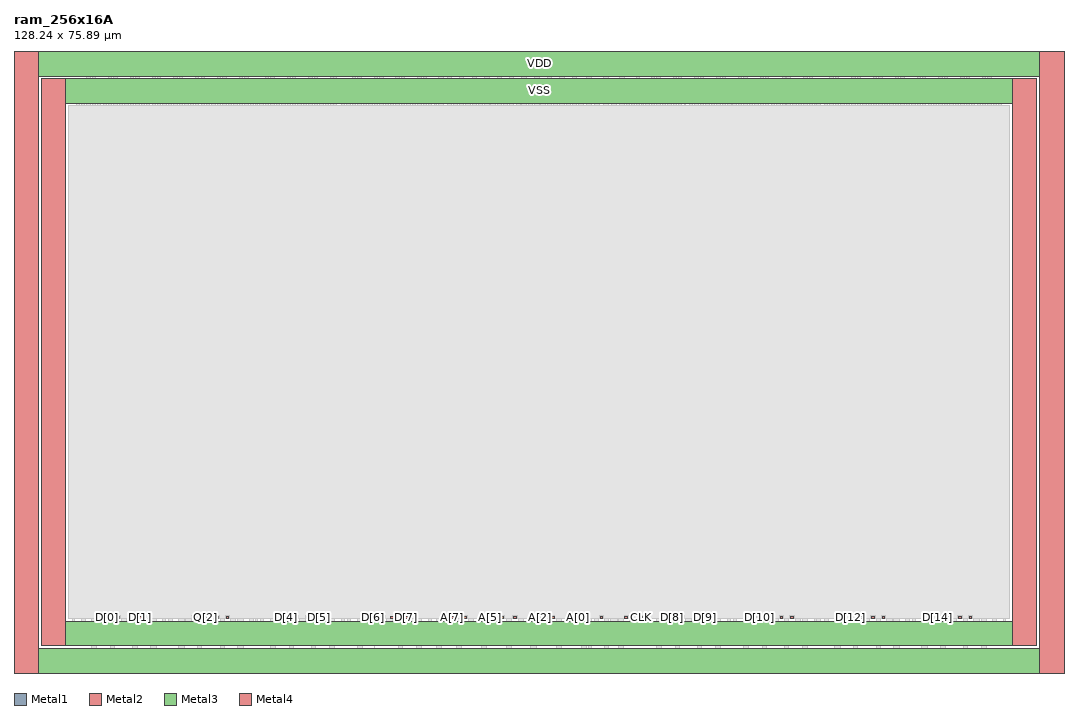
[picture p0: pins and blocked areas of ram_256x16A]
MACRO ram_256x16A
  CLASS RING ;
  FOREIGN ram_256x16A 0 0 ;
  ORIGIN 0 0 ;
  SIZE 128.24 BY 75.89 ;
  SYMMETRY X Y R90 ;
  PIN A[0]
    DIRECTION INPUT ;
    USE SIGNAL ;
    ANTENNAGATEAREA  0.039 ;
    PORT
      LAYER Metal1 ;
        RECT 68.69 6.6 69.02 6.93 ;
      LAYER Metal2 ;
        RECT 68.69 6.6 69.02 6.93 ;
      LAYER Metal3 ;
        RECT 68.69 6.6 69.02 6.93 ;
      LAYER Metal4 ;
        RECT 68.69 6.6 69.02 6.93 ;
      END
    END A[0]
  PIN A[1]
    DIRECTION INPUT ;
    USE SIGNAL ;
    ANTENNAGATEAREA  0.039 ;
    PORT
      LAYER Metal1 ;
        RECT 65.63 6.6 65.96 6.93 ;
      LAYER Metal2 ;
        RECT 65.63 6.6 65.96 6.93 ;
      LAYER Metal3 ;
        RECT 65.63 6.6 65.96 6.93 ;
      LAYER Metal4 ;
        RECT 65.63 6.6 65.96 6.93 ;
      END
    END A[1]
  PIN A[2]
    DIRECTION INPUT ;
    USE SIGNAL ;
    ANTENNAGATEAREA  0.039 ;
    PORT
      LAYER Metal1 ;
        RECT 64.08 6.6 64.41 6.93 ;
      LAYER Metal2 ;
        RECT 64.08 6.6 64.41 6.93 ;
      LAYER Metal3 ;
        RECT 64.08 6.6 64.41 6.93 ;
      LAYER Metal4 ;
        RECT 64.08 6.6 64.41 6.93 ;
      END
    END A[2]
  PIN A[3]
    ANTENNAGATEAREA  0.039 ;
    DIRECTION INPUT ;
    USE SIGNAL ;
    PORT
      LAYER Metal1 ;
        RECT 61.02 6.6 61.35 6.93 ;
      LAYER Metal2 ;
        RECT 61.02 6.6 61.35 6.93 ;
      LAYER Metal3 ;
        RECT 61.02 6.6 61.35 6.93 ;
      LAYER Metal4 ;
        RECT 61.02 6.6 61.35 6.93 ;
      END
    END A[3]
  PIN A[4]
    DIRECTION INPUT ;
    ANTENNAGATEAREA  0.039 ;
    USE SIGNAL ;
    PORT
      LAYER Metal1 ;
        RECT 59.51 6.6 59.84 6.93 ;
      LAYER Metal2 ;
        RECT 59.51 6.6 59.84 6.93 ;
      LAYER Metal3 ;
        RECT 59.51 6.6 59.84 6.93 ;
      LAYER Metal4 ;
        RECT 59.51 6.6 59.84 6.93 ;
      END
    END A[4]
  PIN A[5]
    ANTENNAGATEAREA  0.039 ;
    DIRECTION INPUT ;
    USE SIGNAL ;
    PORT
      LAYER Metal1 ;
        RECT 57.96 6.6 58.29 6.93 ;
      LAYER Metal2 ;
        RECT 57.96 6.6 58.29 6.93 ;
      LAYER Metal3 ;
        RECT 57.96 6.6 58.29 6.93 ;
      LAYER Metal4 ;
        RECT 57.96 6.6 58.29 6.93 ;
      END
    END A[5]
  PIN A[6]
    ANTENNAGATEAREA  0.039 ;
    DIRECTION INPUT ;
    USE SIGNAL ;
    PORT
      LAYER Metal1 ;
        RECT 54.9 6.6 55.23 6.93 ;
      LAYER Metal2 ;
        RECT 54.9 6.6 55.23 6.93 ;
      LAYER Metal3 ;
        RECT 54.9 6.6 55.23 6.93 ;
      LAYER Metal4 ;
        RECT 54.9 6.6 55.23 6.93 ;
      END
    END A[6]
  PIN A[7]
    ANTENNAGATEAREA  0.039 ;
    DIRECTION INPUT ;
    USE SIGNAL ;
    PORT
      LAYER Metal1 ;
        RECT 53.39 6.6 53.72 6.93 ;
      LAYER Metal2 ;
        RECT 53.39 6.6 53.72 6.93 ;
      LAYER Metal3 ;
        RECT 53.39 6.6 53.72 6.93 ;
      LAYER Metal4 ;
        RECT 53.39 6.6 53.72 6.93 ;
      END
    END A[7]
  PIN CEN
    ANTENNAGATEAREA  0.039 ;
    DIRECTION INPUT ;
    USE SIGNAL ;
    PORT
      LAYER Metal1 ;
        RECT 71.59 6.6 71.92 6.93 ;
      LAYER Metal2 ;
        RECT 71.59 6.6 71.92 6.93 ;
      LAYER Metal3 ;
        RECT 71.59 6.6 71.92 6.93 ;
      LAYER Metal4 ;
        RECT 71.59 6.6 71.92 6.93 ;
      END
    END CEN
  PIN CLK
    DIRECTION INPUT ;
    ANTENNAGATEAREA  0.039 ;
    USE CLOCK ;
    PORT
      LAYER Metal1 ;
        RECT 76.47 6.6 76.8 6.93 ;
      LAYER Metal2 ;
        RECT 76.47 6.6 76.8 6.93 ;
      LAYER Metal3 ;
        RECT 76.47 6.6 76.8 6.93 ;
      LAYER Metal4 ;
        RECT 76.47 6.6 76.8 6.93 ;
      END
    END CLK
  PIN D[0]
    ANTENNAGATEAREA  0.039 ;
    DIRECTION INPUT ;
    USE SIGNAL ;
    PORT
      LAYER Metal1 ;
        RECT 11.24 6.6 11.57 6.93 ;
      LAYER Metal2 ;
        RECT 11.24 6.6 11.57 6.93 ;
      LAYER Metal3 ;
        RECT 11.24 6.6 11.57 6.93 ;
      LAYER Metal4 ;
        RECT 11.24 6.6 11.57 6.93 ;
      END
    END D[0]
  PIN D[10]
    DIRECTION INPUT ;
    USE SIGNAL ;
    ANTENNAGATEAREA  0.039 ;
    PORT
      LAYER Metal1 ;
        RECT 90.84 6.6 91.17 6.93 ;
      LAYER Metal2 ;
        RECT 90.84 6.6 91.17 6.93 ;
      LAYER Metal3 ;
        RECT 90.84 6.6 91.17 6.93 ;
      LAYER Metal4 ;
        RECT 90.84 6.6 91.17 6.93 ;
      END
    END D[10]
  PIN D[11]
    DIRECTION INPUT ;
    USE SIGNAL ;
    ANTENNAGATEAREA  0.039 ;
    PORT
      LAYER Metal1 ;
        RECT 94.86 6.6 95.19 6.93 ;
      LAYER Metal2 ;
        RECT 94.86 6.6 95.19 6.93 ;
      LAYER Metal3 ;
        RECT 94.86 6.6 95.19 6.93 ;
      LAYER Metal4 ;
        RECT 94.86 6.6 95.19 6.93 ;
      END
    END D[11]
  PIN D[12]
    DIRECTION INPUT ;
    ANTENNAGATEAREA  0.039 ;
    USE SIGNAL ;
    PORT
      LAYER Metal1 ;
        RECT 102.01 6.6 102.34 6.93 ;
      LAYER Metal2 ;
        RECT 102.01 6.6 102.34 6.93 ;
      LAYER Metal3 ;
        RECT 102.01 6.6 102.34 6.93 ;
      LAYER Metal4 ;
        RECT 102.01 6.6 102.34 6.93 ;
      END
    END D[12]
  PIN D[13]
    DIRECTION INPUT ;
    USE SIGNAL ;
    ANTENNAGATEAREA  0.039 ;
    PORT
      LAYER Metal1 ;
        RECT 106.03 6.6 106.36 6.93 ;
      LAYER Metal2 ;
        RECT 106.03 6.6 106.36 6.93 ;
      LAYER Metal3 ;
        RECT 106.03 6.6 106.36 6.93 ;
      LAYER Metal4 ;
        RECT 106.03 6.6 106.36 6.93 ;
      END
    END D[13]
  PIN D[14]
    DIRECTION INPUT ;
    USE SIGNAL ;
    ANTENNAGATEAREA  0.039 ;
    PORT
      LAYER Metal1 ;
        RECT 112.65 6.6 112.98 6.93 ;
      LAYER Metal2 ;
        RECT 112.65 6.6 112.98 6.93 ;
      LAYER Metal3 ;
        RECT 112.65 6.6 112.98 6.93 ;
      LAYER Metal4 ;
        RECT 112.65 6.6 112.98 6.93 ;
      END
    END D[14]
  PIN D[15]
    ANTENNAGATEAREA  0.039 ;
    DIRECTION INPUT ;
    USE SIGNAL ;
    PORT
      LAYER Metal1 ;
        RECT 116.67 6.6 117.00 6.93 ;
      LAYER Metal2 ;
        RECT 116.67 6.6 117.00 6.93 ;
      LAYER Metal3 ;
        RECT 116.67 6.6 117.00 6.93 ;
      LAYER Metal4 ;
        RECT 116.67 6.6 117.00 6.93 ;
      END
    END D[15]
  PIN D[1]
    DIRECTION INPUT ;
    USE SIGNAL ;
    ANTENNAGATEAREA  0.039 ;
    PORT
      LAYER Metal1 ;
        RECT 15.26 6.6 15.59 6.93 ;
      LAYER Metal2 ;
        RECT 15.26 6.6 15.59 6.93 ;
      LAYER Metal3 ;
        RECT 15.26 6.6 15.59 6.93 ;
      LAYER Metal4 ;
        RECT 15.26 6.6 15.59 6.93 ;
      END
    END D[1]
  PIN D[2]
    DIRECTION INPUT ;
    USE SIGNAL ;
    ANTENNAGATEAREA  0.039 ;
    PORT
      LAYER Metal1 ;
        RECT 21.88 6.6 22.21 6.93 ;
      LAYER Metal2 ;
        RECT 21.88 6.6 22.21 6.93 ;
      LAYER Metal3 ;
        RECT 21.88 6.6 22.21 6.93 ;
      LAYER Metal4 ;
        RECT 21.88 6.6 22.21 6.93 ;
      END
    END D[2]
  PIN D[3]
    DIRECTION INPUT ;
    USE SIGNAL ;
    ANTENNAGATEAREA  0.039 ;
    PORT
      LAYER Metal1 ;
        RECT 25.9 6.6 26.23 6.93 ;
      LAYER Metal2 ;
        RECT 25.9 6.6 26.23 6.93 ;
      LAYER Metal3 ;
        RECT 25.9 6.6 26.23 6.93 ;
      LAYER Metal4 ;
        RECT 25.9 6.6 26.23 6.93 ;
      END
    END D[3]
  PIN D[4]
    DIRECTION INPUT ;
    USE SIGNAL ;
    ANTENNAGATEAREA  0.039 ;
    PORT
      LAYER Metal1 ;
        RECT 33.05 6.6 33.38 6.93 ;
      LAYER Metal2 ;
        RECT 33.05 6.6 33.38 6.93 ;
      LAYER Metal3 ;
        RECT 33.05 6.6 33.38 6.93 ;
      LAYER Metal4 ;
        RECT 33.05 6.6 33.38 6.93 ;
      END
    END D[4]
  PIN D[5]
    DIRECTION INPUT ;
    USE SIGNAL ;
    ANTENNAGATEAREA  0.039 ;
    PORT
      LAYER Metal1 ;
        RECT 37.07 6.6 37.4 6.93 ;
      LAYER Metal2 ;
        RECT 37.07 6.6 37.4 6.93 ;
      LAYER Metal3 ;
        RECT 37.07 6.6 37.4 6.93 ;
      LAYER Metal4 ;
        RECT 37.07 6.6 37.4 6.93 ;
      END
    END D[5]
  PIN D[6]
    DIRECTION INPUT ;
    USE SIGNAL ;
    ANTENNAGATEAREA  0.039 ;
    PORT
      LAYER Metal1 ;
        RECT 43.69 6.6 44.02 6.93 ;
      LAYER Metal2 ;
        RECT 43.69 6.6 44.02 6.93 ;
      LAYER Metal3 ;
        RECT 43.69 6.6 44.02 6.93 ;
      LAYER Metal4 ;
        RECT 43.69 6.6 44.02 6.93 ;
      END
    END D[6]
  PIN D[7]
    DIRECTION INPUT ;
    USE SIGNAL ;
    ANTENNAGATEAREA  0.039 ;
    PORT
      LAYER Metal1 ;
        RECT 47.71 6.6 48.04 6.93 ;
      LAYER Metal2 ;
        RECT 47.71 6.6 48.04 6.93 ;
      LAYER Metal3 ;
        RECT 47.71 6.6 48.04 6.93 ;
      LAYER Metal4 ;
        RECT 47.71 6.6 48.04 6.93 ;
      END
    END D[7]
  PIN D[8]
    DIRECTION INPUT ;
    USE SIGNAL ;
    ANTENNAGATEAREA  0.039 ;
    PORT
      LAYER Metal1 ;
        RECT 80.20 6.6 80.53 6.93 ;
      LAYER Metal2 ;
        RECT 80.20 6.6 80.53 6.93 ;
      LAYER Metal3 ;
        RECT 80.20 6.6 80.53 6.93 ;
      LAYER Metal4 ;
        RECT 80.20 6.6 80.53 6.93 ;
      END
    END D[8]
  PIN D[9]
    DIRECTION INPUT ;
    USE SIGNAL ;
    ANTENNAGATEAREA  0.039 ;
    PORT
      LAYER Metal1 ;
        RECT 84.22 6.6 84.55 6.93 ;
      LAYER Metal2 ;
        RECT 84.22 6.6 84.55 6.93 ;
      LAYER Metal3 ;
        RECT 84.22 6.6 84.55 6.93 ;
      LAYER Metal4 ;
        RECT 84.22 6.6 84.55 6.93 ;
      END
    END D[9]
  PIN Q[0]
    DIRECTION OUTPUT ;
    USE SIGNAL ;
    ANTENNADIFFAREA 1.7285  LAYER Metal1 ;
    PORT
      LAYER Metal1 ;
        RECT 12.53 6.6 12.86 6.93 ;
      LAYER Metal2 ;
        RECT 12.53 6.6 12.86 6.93 ;
      LAYER Metal3 ;
        RECT 12.53 6.6 12.86 6.93 ;
      LAYER Metal4 ;
        RECT 12.53 6.6 12.86 6.93 ;
      END
    END Q[0]
  PIN Q[10]
    DIRECTION OUTPUT ;
    USE SIGNAL ;
    ANTENNADIFFAREA 1.7285  LAYER Metal1 ;
    PORT
      LAYER Metal1 ;
        RECT 92.13 6.6 92.46 6.93 ;
      LAYER Metal2 ;
        RECT 92.13 6.6 92.46 6.93 ;
      LAYER Metal3 ;
        RECT 92.13 6.6 92.46 6.93 ;
      LAYER Metal4 ;
        RECT 92.13 6.6 92.46 6.93 ;
      END
    END Q[10]
  PIN Q[11]
    DIRECTION OUTPUT ;
    USE SIGNAL ;
    ANTENNADIFFAREA 1.7285  LAYER Metal1 ;
    PORT
      LAYER Metal1 ;
        RECT 93.57 6.6 93.90 6.93 ;
      LAYER Metal2 ;
        RECT 93.57 6.6 93.90 6.93 ;
      LAYER Metal3 ;
        RECT 93.57 6.6 93.90 6.93 ;
      LAYER Metal4 ;
        RECT 93.57 6.6 93.90 6.93 ;
      END
    END Q[11]
  PIN Q[12]
    DIRECTION OUTPUT ;
    USE SIGNAL ;
    ANTENNADIFFAREA 1.7285  LAYER Metal1 ;
    PORT
      LAYER Metal1 ;
        RECT 103.30 6.6 103.63 6.93 ;
      LAYER Metal2 ;
        RECT 103.30 6.6 103.63 6.93 ;
      LAYER Metal3 ;
        RECT 103.30 6.6 103.63 6.93 ;
      LAYER Metal4 ;
        RECT 103.30 6.6 103.63 6.93 ;
      END
    END Q[12]
  PIN Q[13]
    DIRECTION OUTPUT ;
    USE SIGNAL ;
    ANTENNADIFFAREA 1.7285  LAYER Metal1 ;
    PORT
      LAYER Metal1 ;
        RECT 104.74 6.6 105.07 6.93 ;
      LAYER Metal2 ;
        RECT 104.74 6.6 105.07 6.93 ;
      LAYER Metal3 ;
        RECT 104.74 6.6 105.07 6.93 ;
      LAYER Metal4 ;
        RECT 104.74 6.6 105.07 6.93 ;
      END
    END Q[13]
  PIN Q[14]
    DIRECTION OUTPUT ;
    USE SIGNAL ;
    ANTENNADIFFAREA 1.7285  LAYER Metal1 ;
    PORT
      LAYER Metal1 ;
        RECT 113.94 6.6 114.27 6.93 ;
      LAYER Metal2 ;
        RECT 113.94 6.6 114.27 6.93 ;
      LAYER Metal3 ;
        RECT 113.94 6.6 114.27 6.93 ;
      LAYER Metal4 ;
        RECT 113.94 6.6 114.27 6.93 ;
      END
    END Q[14]
  PIN Q[15]
    DIRECTION OUTPUT ;
    USE SIGNAL ;
    ANTENNADIFFAREA 1.7285  LAYER Metal1 ;
    PORT
      LAYER Metal1 ;
        RECT 115.38 6.6 115.71 6.93 ;
      LAYER Metal2 ;
        RECT 115.38 6.6 115.71 6.93 ;
      LAYER Metal3 ;
        RECT 115.38 6.6 115.71 6.93 ;
      LAYER Metal4 ;
        RECT 115.38 6.6 115.71 6.93 ;
      END
    END Q[15]
  PIN Q[1]
    DIRECTION OUTPUT ;
    USE SIGNAL ;
    ANTENNADIFFAREA 1.7285  LAYER Metal1 ;
    PORT
      LAYER Metal1 ;
        RECT 13.97 6.6 14.3 6.93 ;
      LAYER Metal2 ;
        RECT 13.97 6.6 14.3 6.93 ;
      LAYER Metal3 ;
        RECT 13.97 6.6 14.3 6.93 ;
      LAYER Metal4 ;
        RECT 13.97 6.6 14.3 6.93 ;
      END
    END Q[1]
  PIN Q[2]
    DIRECTION OUTPUT ;
    USE SIGNAL ;
    ANTENNADIFFAREA 1.7285  LAYER Metal1 ;
    PORT
      LAYER Metal1 ;
        RECT 23.17 6.6 23.5 6.93 ;
      LAYER Metal2 ;
        RECT 23.17 6.6 23.5 6.93 ;
      LAYER Metal3 ;
        RECT 23.17 6.6 23.5 6.93 ;
      LAYER Metal4 ;
        RECT 23.17 6.6 23.5 6.93 ;
      END
    END Q[2]
  PIN Q[3]
    DIRECTION OUTPUT ;
    USE SIGNAL ;
    ANTENNADIFFAREA 1.7285  LAYER Metal1 ;
    PORT
      LAYER Metal1 ;
        RECT 24.61 6.6 24.94 6.93 ;
      LAYER Metal2 ;
        RECT 24.61 6.6 24.94 6.93 ;
      LAYER Metal3 ;
        RECT 24.61 6.6 24.94 6.93 ;
      LAYER Metal4 ;
        RECT 24.61 6.6 24.94 6.93 ;
      END
    END Q[3]
  PIN Q[4]
    DIRECTION OUTPUT ;
    USE SIGNAL ;
    ANTENNADIFFAREA 1.7285  LAYER Metal1 ;
    PORT
      LAYER Metal1 ;
        RECT 34.34 6.6 34.67 6.93 ;
      LAYER Metal2 ;
        RECT 34.34 6.6 34.67 6.93 ;
      LAYER Metal3 ;
        RECT 34.34 6.6 34.67 6.93 ;
      LAYER Metal4 ;
        RECT 34.34 6.6 34.67 6.93 ;
      END
    END Q[4]
  PIN Q[5]
    DIRECTION OUTPUT ;
    USE SIGNAL ;
    ANTENNADIFFAREA 1.7285  LAYER Metal1 ;
    PORT
      LAYER Metal1 ;
        RECT 35.78 6.6 36.11 6.93 ;
      LAYER Metal2 ;
        RECT 35.78 6.6 36.11 6.93 ;
      LAYER Metal3 ;
        RECT 35.78 6.6 36.11 6.93 ;
      LAYER Metal4 ;
        RECT 35.78 6.6 36.11 6.93 ;
      END
    END Q[5]
  PIN Q[6]
    DIRECTION OUTPUT ;
    USE SIGNAL ;
    ANTENNADIFFAREA 1.7285  LAYER Metal1 ;
    PORT
      LAYER Metal1 ;
        RECT 44.98 6.6 45.31 6.93 ;
      LAYER Metal2 ;
        RECT 44.98 6.6 45.31 6.93 ;
      LAYER Metal3 ;
        RECT 44.98 6.6 45.31 6.93 ;
      LAYER Metal4 ;
        RECT 44.98 6.6 45.31 6.93 ;
      END
    END Q[6]
  PIN Q[7]
    DIRECTION OUTPUT ;
    USE SIGNAL ;
    ANTENNADIFFAREA 1.7285  LAYER Metal1 ;
    PORT
      LAYER Metal1 ;
        RECT 46.42 6.6 46. 6.93 ;
      LAYER Metal2 ;
        RECT 46.42 6.6 46. 6.93 ;
      LAYER Metal3 ;
        RECT 46.42 6.6 46. 6.93 ;
      LAYER Metal4 ;
        RECT 46.42 6.6 46. 6.93 ;
      END
    END Q[7]
  PIN Q[8]
    DIRECTION OUTPUT ;
    USE SIGNAL ;
    ANTENNADIFFAREA 1.7285  LAYER Metal1 ;
    PORT
      LAYER Metal1 ;
        RECT 81.49 6.6 81.82 6.93 ;
      LAYER Metal2 ;
        RECT 81.49 6.6 81.82 6.93 ;
      LAYER Metal3 ;
        RECT 81.49 6.6 81.82 6.93 ;
      LAYER Metal4 ;
        RECT 81.49 6.6 81.82 6.93 ;
      END
    END Q[8]
  PIN Q[9]
    DIRECTION OUTPUT ;
    USE SIGNAL ;
    ANTENNADIFFAREA 1.7285  LAYER Metal1 ;
    PORT
      LAYER Metal1 ;
        RECT 82.93 6.6 83.26 6.93 ;
      LAYER Metal2 ;
        RECT 82.93 6.6 83.26 6.93 ;
      LAYER Metal3 ;
        RECT 82.93 6.6 83.26 6.93 ;
      LAYER Metal4 ;
        RECT 82.93 6.6 83.26 6.93 ;
      END
    END Q[9]
  PIN WEN
    DIRECTION INPUT ;
    USE SIGNAL ;
    ANTENNAGATEAREA  0.039 ;
    PORT
      LAYER Metal1 ;
        RECT 74.62 6.6 74.95 6.93 ;
      LAYER Metal2 ;
        RECT 74.62 6.6 74.95 6.93 ;
      LAYER Metal3 ;
        RECT 74.62 6.6 74.95 6.93 ;
      LAYER Metal4 ;
        RECT 74.62 6.6 74.95 6.93 ;
      END
    END WEN
  PIN VDD
    DIRECTION INOUT ;
    USE POWER ;
    SHAPE RING ;
    PORT
      LAYER Metal3 ;
        RECT 128.24 72.89 0 75.89 ;
      LAYER Metal3 ;
        RECT 0 0 128.24 3 ;
      LAYER Metal4 ;
        RECT 125.24 0 128.24 75.89 ;
      LAYER Metal4 ;
        RECT 0 75.89 3 0 ;
      END
    END VDD
  PIN VSS
    DIRECTION INOUT ;
    USE GROUND ;
    SHAPE RING ;
    PORT
      LAYER Metal3 ;
        RECT 124.94 69.59 3.3 72.59 ;
      LAYER Metal3 ;
        RECT 3.3 3.3 124.94 6.3 ;
      LAYER Metal4 ;
        RECT 121.94 3.3 124.94 72.59 ;
      LAYER Metal4 ;
        RECT 3.3 72.59 6.3 3.3 ;
      END
    END VSS
  OBS
    LAYER OVERLAP ;
        RECT 6.6 6.6 121.64 69.29 ;
    LAYER Via1 ;
        RECT 6.6 6.6 121.64 69.29 ;
    LAYER Via2 ;
        RECT 6.6 6.6 121.64 69.29 ;
    LAYER Via3 ;
        RECT 6.6 6.6 121.64 69.29 ;
    LAYER Via4 ;
        RECT 6.6 6.6 121.64 69.29 ;
    LAYER Metal1 ;
POLYGON 6.6 69.29 6.6 6.6 11.15 6.6 11.15 7.02 11.66 7.02 
11.66 6.6 12.44 6.6 12.44 7.02 12.95 7.02 12.95 6.6 13.88 6.6 
13.88 7.02 14.39 7.02 14.39 6.6 15.17 6.6 15.17 7.02 15.68 7.02 
15.68 6.6 21.79 6.6 21.79 7.02 22.3 7.02 22.3 6.6 23.08 6.6 
23.08 7.02 23.59 7.02 23.59 6.6 24.52 6.6 24.52 7.02 25.03 7.02 
25.03 6.6 25.81 6.6 25.81 7.02 26.32 7.02 26.32 6.6 32.96 6.6 
32.96 7.02 33.47 7.02 33.47 6.6 34. 6.6 34. 7.02 34.76 7.02 
34.76 6.6 35.69 6.6 35.69 7.02 36.2 7.02 36.2 6.6 36.98 6.6 
36.98 7.02 37.49 7.02 37.49 6.6 43.6 6.6 43.6 7.02 44.11 7.02 
44.11 6.6 44.89 6.6 44.89 7.02 45.4 7.02 45.4 6.6 46.33 6.6 
46.33 7.02 46.84 7.02 46.84 6.6 47.62 6.6 47.62 7.02 48.13 7.02 
48.13 6.6 53.3 6.6 53.3 7.02 53.81 7.02 53.81 6.6 54.81 6.6 
54.81 7.02 55.32 7.02 55.32 6.6 57.87 6.6 57.87 7.02 
58.38 7.02 58.38 6.6 59.42 6.6 59.42 7.02 59.93 7.02 
59.93 6.6 60.93 6.6 60.93 7.02 61.44 7.02 61.44 6.6 
63.99 6.6 63.99 7.02 64.5 7.02 64.5 6.6 65.54 6.6 65.54 7.02 
66.05 7.02 66.05 6.6 68.6 6.6 68.6 7.02 69.11 7.02 69.11 6.6 
71.50 6.6 71.50 7.02 72.01 7.02 72.01 6.6 74.53 6.6 
74.53 7.02 75.04 7.02 75.04 6.6 76.38 6.6 76.38 7.02 
76.89 7.02 76.89 6.6 80.11 6.6 80.11 7.02 80.62 7.02 
80.62 6.6 81.40 6.6 81.40 7.02 81.91 7.02 81.91 6.6 
82.84 6.6 82.84 7.02 83.35 7.02 83.35 6.6 84.13 6.6 
84.13 7.02 84.64 7.02 84.64 6.6 90. 6.6 90. 7.02 
91.26 7.02 91.26 6.6 92.04 6.6 92.04 7.02 92.55 7.02 
92.55 6.6 93.48 6.6 93.48 7.02 93.99 7.02 93.99 6.6 
94.77 6.6 94.77 7.02 95.28 7.02 95.28 6.6 101.92 6.6 
101.92 7.02 102.43 7.02 102.43 6.6 103.21 6.6 103.21 7.02 
103.72 7.02 103.72 6.6 104.65 6.6 104.65 7.02 105.16 7.02 
105.16 6.6 105.94 6.6 105.94 7.02 106.45 7.02 106.45 6.6 
112.56 6.6 112.56 7.02 113.07 7.02 113.07 6.6 113.85 6.6 
113.85 7.02 114.36 7.02 114.36 6.6 115.29 6.6 115.29 7.02 
115.80 7.02 115.80 6.6 116.58 6.6 116.58 7.02 117.09 7.02 
117.09 6.6 121.64 6.6 121.64 69.29 ;
    LAYER Metal2 ;
POLYGON 6.6 69.29 6.6 6.6 11.135 6.6 11.135 7.035 11.6 7.035 
11.6 6.6 12.4 6.6 12.4 7.035 12.965 7.035 12.965 6.6 13.865 6.6 
13.865 7.035 14.405 7.035 14.405 6.6 15.155 6.6 15.155 7.035 15.695 7.035 
15.695 6.6 21.7 6.6 21.7 7.035 22.315 7.035 22.315 6.6 23.065 6.6 
23.065 7.035 23.605 7.035 23.605 6.6 24.505 6.6 24.505 7.035 25.045 7.035 
25.045 6.6 25.795 6.6 25.795 7.035 26.335 7.035 26.335 6.6 32.945 6.6 
32.945 7.035 33.485 7.035 33.485 6.6 34.235 6.6 34.235 7.035 34.7 7.035 
34.7 6.6 35.6 6.6 35.6 7.035 36.215 7.035 36.215 6.6 36.965 6.6 
36.965 7.035 37.505 7.035 37.505 6.6 43.585 6.6 43.585 7.035 44.1 7.035 
44.1 6.6 44.8 6.6 44.8 7.035 45.415 7.035 45.415 6.6 46.315 6.6 
46.315 7.035 46.855 7.035 46.855 6.6 47.605 6.6 47.605 7.035 48.145 7.035 
48.145 6.6 53.285 6.6 53.285 7.035 53.8 7.035 53.8 6.6 
54.795 6.6 54.795 7.035 55.335 7.035 55.335 6.6 57.855 6.6 
57.855 7.035 58.395 7.035 58.395 6.6 59.405 6.6 59.405 7.035 
59.945 7.035 59.945 6.6 60.915 6.6 60.915 7.035 61.455 7.035 
61.455 6.6 63.9 6.6 63.9 7.035 64.515 7.035 64.515 6.6 
65.5 6.6 65.5 7.035 66.065 7.035 66.065 6.6 68.585 6.6 
68.585 7.035 69.1 7.035 69.1 6.6 71.49 6.6 71.49 7.035 
72.03 7.035 72.03 6.6 74.515 6.6 74.515 7.035 75.055 7.035 
75.055 6.6 76.365 6.6 76.365 7.035 76.905 7.035 76.905 6.6 
80.09 6.6 80.09 7.035 80.63 7.035 80.63 6.6 81.38 6.6 
81.38 7.035 81.92 7.035 81.92 6.6 82.82 6.6 82.82 7.035 
83.36 7.035 83.36 6.6 84.11 6.6 84.11 7.035 84.65 7.035 
84.65 6.6 90.73 6.6 90.73 7.035 91.27 7.035 91.27 6.6 
92.02 6.6 92.02 7.035 92.56 7.035 92.56 6.6 93.46 6.6 
93.46 7.035 94.00 7.035 94.00 6.6 94.75 6.6 94.75 7.035 
95.29 7.035 95.29 6.6 101.90 6.6 101.90 7.035 102.44 7.035 
102.44 6.6 103.19 6.6 103.19 7.035 103.73 7.035 103.73 6.6 
104.63 6.6 104.63 7.035 105.17 7.035 105.17 6.6 105.92 6.6 
105.92 7.035 106.46 7.035 106.46 6.6 112.54 6.6 112.54 7.035 
113.08 7.035 113.08 6.6 113.83 6.6 113.83 7.035 114.37 7.035 
114.37 6.6 115.27 6.6 115.27 7.035 115.81 7.035 115.81 6.6 
116.56 6.6 116.56 7.035 117.10 7.035 117.10 6.6 121.64 6.6 
121.64 69.29 ;
    LAYER Metal3 ;
POLYGON 6.6 69.29 6.6 6.6 11.135 6.6 11.135 7.035 11.6 7.035 
11.6 6.6 12.4 6.6 12.4 7.035 12.965 7.035 12.965 6.6 13.865 6.6 
13.865 7.035 14.405 7.035 14.405 6.6 15.155 6.6 15.155 7.035 15.695 7.035 
15.695 6.6 21.7 6.6 21.7 7.035 22.315 7.035 22.315 6.6 23.065 6.6 
23.065 7.035 23.605 7.035 23.605 6.6 24.505 6.6 24.505 7.035 25.045 7.035 
25.045 6.6 25.795 6.6 25.795 7.035 26.335 7.035 26.335 6.6 32.945 6.6 
32.945 7.035 33.485 7.035 33.485 6.6 34.235 6.6 34.235 7.035 34.7 7.035 
34.7 6.6 35.6 6.6 35.6 7.035 36.215 7.035 36.215 6.6 36.965 6.6 
36.965 7.035 37.505 7.035 37.505 6.6 43.585 6.6 43.585 7.035 44.1 7.035 
44.1 6.6 44.8 6.6 44.8 7.035 45.415 7.035 45.415 6.6 46.315 6.6 
46.315 7.035 46.855 7.035 46.855 6.6 47.605 6.6 47.605 7.035 48.145 7.035 
48.145 6.6 53.285 6.6 53.285 7.035 53.8 7.035 53.8 6.6 
54.795 6.6 54.795 7.035 55.335 7.035 55.335 6.6 57.855 6.6 
57.855 7.035 58.395 7.035 58.395 6.6 59.405 6.6 59.405 7.035 
59.945 7.035 59.945 6.6 60.915 6.6 60.915 7.035 61.455 7.035 
61.455 6.6 63.9 6.6 63.9 7.035 64.515 7.035 64.515 6.6 
65.5 6.6 65.5 7.035 66.065 7.035 66.065 6.6 68.585 6.6 
68.585 7.035 69.1 7.035 69.1 6.6 71.49 6.6 71.49 7.035 
72.03 7.035 72.03 6.6 74.515 6.6 74.515 7.035 75.055 7.035 
75.055 6.6 76.365 6.6 76.365 7.035 76.905 7.035 76.905 6.6 
80.09 6.6 80.09 7.035 80.63 7.035 80.63 6.6 81.38 6.6 
81.38 7.035 81.92 7.035 81.92 6.6 82.82 6.6 82.82 7.035 
83.36 7.035 83.36 6.6 84.11 6.6 84.11 7.035 84.65 7.035 
84.65 6.6 90.73 6.6 90.73 7.035 91.27 7.035 91.27 6.6 
92.02 6.6 92.02 7.035 92.56 7.035 92.56 6.6 93.46 6.6 
93.46 7.035 94.00 7.035 94.00 6.6 94.75 6.6 94.75 7.035 
95.29 7.035 95.29 6.6 101.90 6.6 101.90 7.035 102.44 7.035 
102.44 6.6 103.19 6.6 103.19 7.035 103.73 7.035 103.73 6.6 
104.63 6.6 104.63 7.035 105.17 7.035 105.17 6.6 105.92 6.6 
105.92 7.035 106.46 7.035 106.46 6.6 112.54 6.6 112.54 7.035 
113.08 7.035 113.08 6.6 113.83 6.6 113.83 7.035 114.37 7.035 
114.37 6.6 115.27 6.6 115.27 7.035 115.81 7.035 115.81 6.6 
116.56 6.6 116.56 7.035 117.10 7.035 117.10 6.6 121.64 6.6 
121.64 69.29 ;
    LAYER Metal4 ;
POLYGON 6.6 69.29 6.6 6.6 11.135 6.6 11.135 7.035 11.6 7.035 
11.6 6.6 12.4 6.6 12.4 7.035 12.965 7.035 12.965 6.6 13.865 6.6 
13.865 7.035 14.405 7.035 14.405 6.6 15.155 6.6 15.155 7.035 15.695 7.035 
15.695 6.6 21.7 6.6 21.7 7.035 22.315 7.035 22.315 6.6 23.065 6.6 
23.065 7.035 23.605 7.035 23.605 6.6 24.505 6.6 24.505 7.035 25.045 7.035 
25.045 6.6 25.795 6.6 25.795 7.035 26.335 7.035 26.335 6.6 32.945 6.6 
32.945 7.035 33.485 7.035 33.485 6.6 34.235 6.6 34.235 7.035 34.7 7.035 
34.7 6.6 35.6 6.6 35.6 7.035 36.215 7.035 36.215 6.6 36.965 6.6 
36.965 7.035 37.505 7.035 37.505 6.6 43.585 6.6 43.585 7.035 44.1 7.035 
44.1 6.6 44.8 6.6 44.8 7.035 45.415 7.035 45.415 6.6 46.315 6.6 
46.315 7.035 46.855 7.035 46.855 6.6 47.605 6.6 47.605 7.035 48.145 7.035 
48.145 6.6 53.285 6.6 53.285 7.035 53.8 7.035 53.8 6.6 
54.795 6.6 54.795 7.035 55.335 7.035 55.335 6.6 57.855 6.6 
57.855 7.035 58.395 7.035 58.395 6.6 59.405 6.6 59.405 7.035 
59.945 7.035 59.945 6.6 60.915 6.6 60.915 7.035 61.455 7.035 
61.455 6.6 63.9 6.6 63.9 7.035 64.515 7.035 64.515 6.6 
65.5 6.6 65.5 7.035 66.065 7.035 66.065 6.6 68.585 6.6 
68.585 7.035 69.1 7.035 69.1 6.6 71.49 6.6 71.49 7.035 
72.03 7.035 72.03 6.6 74.515 6.6 74.515 7.035 75.055 7.035 
75.055 6.6 76.365 6.6 76.365 7.035 76.905 7.035 76.905 6.6 
80.09 6.6 80.09 7.035 80.63 7.035 80.63 6.6 81.38 6.6 
81.38 7.035 81.92 7.035 81.92 6.6 82.82 6.6 82.82 7.035 
83.36 7.035 83.36 6.6 84.11 6.6 84.11 7.035 84.65 7.035 
84.65 6.6 90.73 6.6 90.73 7.035 91.27 7.035 91.27 6.6 
92.02 6.6 92.02 7.035 92.56 7.035 92.56 6.6 93.46 6.6 
93.46 7.035 94.00 7.035 94.00 6.6 94.75 6.6 94.75 7.035 
95.29 7.035 95.29 6.6 101.90 6.6 101.90 7.035 102.44 7.035 
102.44 6.6 103.19 6.6 103.19 7.035 103.73 7.035 103.73 6.6 
104.63 6.6 104.63 7.035 105.17 7.035 105.17 6.6 105.92 6.6 
105.92 7.035 106.46 7.035 106.46 6.6 112.54 6.6 112.54 7.035 
113.08 7.035 113.08 6.6 113.83 6.6 113.83 7.035 114.37 7.035 
114.37 6.6 115.27 6.6 115.27 7.035 115.81 7.035 115.81 6.6 
116.56 6.6 116.56 7.035 117.10 7.035 117.10 6.6 121.64 6.6 
121.64 69.29 ;
    LAYER Metal4 ;
        RECT 8.88 69.29 9.29 75.89 ;
    LAYER Metal4 ;
        RECT 9.55 69.29 9.96 75.89 ;
    LAYER Metal4 ;
        RECT 11.54 69.29 11.95 75.89 ;
    LAYER Metal4 ;
        RECT 12.21 69.29 12.62 75.89 ;
    LAYER Metal4 ;
        RECT 14.20 69.29 14.61 75.89 ;
    LAYER Metal4 ;
        RECT 14.87 69.29 15.28 75.89 ;
    LAYER Metal4 ;
        RECT 16.86 69.29 17.27 75.89 ;
    LAYER Metal4 ;
        RECT 17.53 69.29 17.94 75.89 ;
    LAYER Metal4 ;
        RECT 19.52 69.29 19.93 75.89 ;
    LAYER Metal4 ;
        RECT 20.19 69.29 20.60 75.89 ;
    LAYER Metal4 ;
        RECT 22.18 69.29 22.59 75.89 ;
    LAYER Metal4 ;
        RECT 22.85 69.29 23.26 75.89 ;
    LAYER Metal4 ;
        RECT 24.84 69.29 25.25 75.89 ;
    LAYER Metal4 ;
        RECT 25.51 69.29 25.92 75.89 ;
    LAYER Metal4 ;
        RECT 27.50 69.29 27.91 75.89 ;
    LAYER Metal4 ;
        RECT 28.17 69.29 28.58 75.89 ;
    LAYER Metal4 ;
        RECT 30.69 69.29 31.10 75.89 ;
    LAYER Metal4 ;
        RECT 31.36 69.29 31.77 75.89 ;
    LAYER Metal4 ;
        RECT 33.35 69.29 33.76 75.89 ;
    LAYER Metal4 ;
        RECT 34.02 69.29 34.43 75.89 ;
    LAYER Metal4 ;
        RECT 36.01 69.29 36.42 75.89 ;
    LAYER Metal4 ;
        RECT 36.68 69.29 37.09 75.89 ;
    LAYER Metal4 ;
        RECT 38.67 69.29 39.08 75.89 ;
    LAYER Metal4 ;
        RECT 39.34 69.29 39. 75.89 ;
    LAYER Metal4 ;
        RECT 41.33 69.29 41.74 75.89 ;
    LAYER Metal4 ;
        RECT 42.00 69.29 42.41 75.89 ;
    LAYER Metal4 ;
        RECT 43.99 69.29 44.40 75.89 ;
    LAYER Metal4 ;
        RECT 44.66 69.29 45.07 75.89 ;
    LAYER Metal4 ;
        RECT 46.65 69.29 47.06 75.89 ;
    LAYER Metal4 ;
        RECT 47.32 69.29 47.73 75.89 ;
    LAYER Metal4 ;
        RECT 49.31 69.29 49.72 75.89 ;
    LAYER Metal4 ;
        RECT 49.98 69.29 50.39 75.89 ;
    LAYER Metal4 ;
        RECT 51.85 69.29 52.48 75.89 ;
    LAYER Metal4 ;
        RECT 52.895 69.29 53.4 75.89 ;
    LAYER Metal4 ;
        RECT 54.4 69.29 54.955 75.89 ;
    LAYER Metal4 ;
        RECT 55.955 69.29 56.485 75.89 ;
    LAYER Metal4 ;
        RECT 57.485 69.29 58.015 75.89 ;
    LAYER Metal4 ;
        RECT 59.015 69.29 59.545 75.89 ;
    LAYER Metal4 ;
        RECT 60.545 69.29 61.0 75.89 ;
    LAYER Metal4 ;
        RECT 62.0 69.29 62.605 75.89 ;
    LAYER Metal4 ;
        RECT 63.605 69.29 64.135 75.89 ;
    LAYER Metal4 ;
        RECT 65.135 69.29 65.665 75.89 ;
    LAYER Metal4 ;
        RECT 66.665 69.29 67.195 75.89 ;
    LAYER Metal4 ;
        RECT 68.195 69.29 68.7 75.89 ;
    LAYER Metal4 ;
        RECT 69.91 69.29 70.54 75.89 ;
    LAYER Metal4 ;
        RECT 71.95 69.29 72.58 75.89 ;
    LAYER Metal4 ;
        RECT 73.99 69.29 74.62 75.89 ;
    LAYER Metal4 ;
        RECT 75.99 69.29 76.4 75.89 ;
    LAYER Metal4 ;
        RECT 77.85 69.29 78.26 75.89 ;
    LAYER Metal4 ;
        RECT 78.515 69.29 78.9 75.89 ;
    LAYER Metal4 ;
        RECT 80.51 69.29 80.92 75.89 ;
    LAYER Metal4 ;
        RECT 81.1 69.29 81.585 75.89 ;
    LAYER Metal4 ;
        RECT 83.17 69.29 83.58 75.89 ;
    LAYER Metal4 ;
        RECT 83.835 69.29 84.245 75.89 ;
    LAYER Metal4 ;
        RECT 85.83 69.29 86.24 75.89 ;
    LAYER Metal4 ;
        RECT 86.495 69.29 86.905 75.89 ;
    LAYER Metal4 ;
        RECT 88.49 69.29 88.9 75.89 ;
    LAYER Metal4 ;
        RECT 89.155 69.29 89.565 75.89 ;
    LAYER Metal4 ;
        RECT 91.15 69.29 91.56 75.89 ;
    LAYER Metal4 ;
        RECT 91.815 69.29 92.2 75.89 ;
    LAYER Metal4 ;
        RECT 93.81 69.29 94.22 75.89 ;
    LAYER Metal4 ;
        RECT 94.4 69.29 94.885 75.89 ;
    LAYER Metal4 ;
        RECT 96.47 69.29 96.88 75.89 ;
    LAYER Metal4 ;
        RECT 97.135 69.29 97.545 75.89 ;
    LAYER Metal4 ;
        RECT 99.66 69.29 100.07 75.89 ;
    LAYER Metal4 ;
        RECT 100.3 69.29 100.735 75.89 ;
    LAYER Metal4 ;
        RECT 102.32 69.29 102.73 75.89 ;
    LAYER Metal4 ;
        RECT 102.985 69.29 103.395 75.89 ;
    LAYER Metal4 ;
        RECT 104.98 69.29 105.39 75.89 ;
    LAYER Metal4 ;
        RECT 105.645 69.29 106.055 75.89 ;
    LAYER Metal4 ;
        RECT 107.64 69.29 108.05 75.89 ;
    LAYER Metal4 ;
        RECT 108.305 69.29 108.715 75.89 ;
    LAYER Metal4 ;
        RECT 110.3 69.29 110.71 75.89 ;
    LAYER Metal4 ;
        RECT 110.965 69.29 111.3 75.89 ;
    LAYER Metal4 ;
        RECT 112.96 69.29 113.37 75.89 ;
    LAYER Metal4 ;
        RECT 113.6 69.29 114.035 75.89 ;
    LAYER Metal4 ;
        RECT 115.62 69.29 116.03 75.89 ;
    LAYER Metal4 ;
        RECT 116.285 69.29 116.695 75.89 ;
    LAYER Metal4 ;
        RECT 118.28 69.29 118.69 75.89 ;
    LAYER Metal4 ;
        RECT 118.945 69.29 119.355 75.89 ;
    LAYER Metal4 ;
        RECT 9.48 6.6 10.13 0 ;
    LAYER Metal4 ;
        RECT 11.8 6.6 12.3 0 ;
    LAYER Metal4 ;
        RECT 14.53 6.6 15.03 0 ;
    LAYER Metal4 ;
        RECT 16.7 6.6 17.35 0 ;
    LAYER Metal4 ;
        RECT 20.12 6.6 20.77 0 ;
    LAYER Metal4 ;
        RECT 22.44 6.6 22.94 0 ;
    LAYER Metal4 ;
        RECT 25.17 6.6 25.67 0 ;
    LAYER Metal4 ;
        RECT 27.34 6.6 27.99 0 ;
    LAYER Metal4 ;
        RECT 31.29 6.6 31.94 0 ;
    LAYER Metal4 ;
        RECT 33.61 6.6 34.11 0 ;
    LAYER Metal4 ;
        RECT 36.34 6.6 36.84 0 ;
    LAYER Metal4 ;
        RECT 38.51 6.6 39.16 0 ;
    LAYER Metal4 ;
        RECT 41.93 6.6 42.58 0 ;
    LAYER Metal4 ;
        RECT 44. 6.6 44. 0 ;
    LAYER Metal4 ;
        RECT 46.98 6.6 47.48 0 ;
    LAYER Metal4 ;
        RECT 49.15 6.6 49.8 0 ;
    LAYER Metal4 ;
        RECT 51.58 6.6 52.21 0 ;
    LAYER Metal4 ;
        RECT 53.995 6.6 54.6 0 ;
    LAYER Metal4 ;
        RECT 57.055 6.6 57.685 0 ;
    LAYER Metal4 ;
        RECT 60.115 6.6 60.745 0 ;
    LAYER Metal4 ;
        RECT 63.1 6.6 63.805 0 ;
    LAYER Metal4 ;
        RECT 66.235 6.6 66.865 0 ;
    LAYER Metal4 ;
        RECT 69.295 6.6 69.9 0 ;
    LAYER Metal4 ;
        RECT 70.155 6.6 70.505 0 ;
    LAYER Metal4 ;
        RECT 72.15 6.6 72.56 0 ;
    LAYER Metal4 ;
        RECT 73.89 6.6 74.39 0 ;
    LAYER Metal4 ;
        RECT 78.44 6.6 79.09 0 ;
    LAYER Metal4 ;
        RECT 80.76 6.6 81.26 0 ;
    LAYER Metal4 ;
        RECT 83.49 6.6 83.99 0 ;
    LAYER Metal4 ;
        RECT 85.66 6.6 86.31 0 ;
    LAYER Metal4 ;
        RECT 89.08 6.6 89.73 0 ;
    LAYER Metal4 ;
        RECT 91.40 6.6 91.90 0 ;
    LAYER Metal4 ;
        RECT 94.13 6.6 94.63 0 ;
    LAYER Metal4 ;
        RECT 96.30 6.6 96.95 0 ;
    LAYER Metal4 ;
        RECT 100.25 6.6 100.90 0 ;
    LAYER Metal4 ;
        RECT 102.57 6.6 103.07 0 ;
    LAYER Metal4 ;
        RECT 105.30 6.6 105.80 0 ;
    LAYER Metal4 ;
        RECT 107.47 6.6 108.12 0 ;
    LAYER Metal4 ;
        RECT 110.89 6.6 111.54 0 ;
    LAYER Metal4 ;
        RECT 113.21 6.6 113.71 0 ;
    LAYER Metal4 ;
        RECT 115.94 6.6 116.44 0 ;
    LAYER Metal4 ;
        RECT 118.11 6.6 118.76 0 ;
    LAYER Metal4 ;
        RECT 7.68 69.29 7.98 72.59 ;
    LAYER Metal4 ;
        RECT 8.22 69.29 8.63 72.59 ;
    LAYER Metal4 ;
        RECT 10.21 69.29 10.62 72.59 ;
    LAYER Metal4 ;
        RECT 10.88 69.29 11.29 72.59 ;
    LAYER Metal4 ;
        RECT 12.87 69.29 13.28 72.59 ;
    LAYER Metal4 ;
        RECT 13.54 69.29 13.95 72.59 ;
    LAYER Metal4 ;
        RECT 15.53 69.29 15.94 72.59 ;
    LAYER Metal4 ;
        RECT 16.20 69.29 16.61 72.59 ;
    LAYER Metal4 ;
        RECT 18.19 69.29 18.60 72.59 ;
    LAYER Metal4 ;
        RECT 18.86 69.29 19.27 72.59 ;
    LAYER Metal4 ;
        RECT 20.85 69.29 21.26 72.59 ;
    LAYER Metal4 ;
        RECT 21.52 69.29 21.93 72.59 ;
    LAYER Metal4 ;
        RECT 23.51 69.29 23.92 72.59 ;
    LAYER Metal4 ;
        RECT 24.18 69.29 24.59 72.59 ;
    LAYER Metal4 ;
        RECT 26.17 69.29 26.58 72.59 ;
    LAYER Metal4 ;
        RECT 26.84 69.29 27.25 72.59 ;
    LAYER Metal4 ;
        RECT 28.83 69.29 29.24 72.59 ;
    LAYER Metal4 ;
        RECT 29.49 69.29 29.79 72.59 ;
    LAYER Metal4 ;
        RECT 30.03 69.29 30.44 72.59 ;
    LAYER Metal4 ;
        RECT 32.02 69.29 32.43 72.59 ;
    LAYER Metal4 ;
        RECT 32.69 69.29 33.10 72.59 ;
    LAYER Metal4 ;
        RECT 34.68 69.29 35.09 72.59 ;
    LAYER Metal4 ;
        RECT 35.35 69.29 35.76 72.59 ;
    LAYER Metal4 ;
        RECT 37.34 69.29 37.75 72.59 ;
    LAYER Metal4 ;
        RECT 38.01 69.29 38.42 72.59 ;
    LAYER Metal4 ;
        RECT 40.00 69.29 40.41 72.59 ;
    LAYER Metal4 ;
        RECT 40.67 69.29 41.08 72.59 ;
    LAYER Metal4 ;
        RECT 42.66 69.29 43.07 72.59 ;
    LAYER Metal4 ;
        RECT 43.33 69.29 43.74 72.59 ;
    LAYER Metal4 ;
        RECT 45.32 69.29 45.73 72.59 ;
    LAYER Metal4 ;
        RECT 45.99 69.29 46.40 72.59 ;
    LAYER Metal4 ;
        RECT 47.98 69.29 48.39 72.59 ;
    LAYER Metal4 ;
        RECT 48.65 69.29 49.06 72.59 ;
    LAYER Metal4 ;
        RECT 50.64 69.29 51.05 72.59 ;
    LAYER Metal4 ;
        RECT 51.3 69.29 51.6 72.59 ;
    LAYER Metal4 ;
        RECT 53.665 69.29 54.195 72.59 ;
    LAYER Metal4 ;
        RECT 55.195 69.29 55.7 72.59 ;
    LAYER Metal4 ;
        RECT 56.7 69.29 57.255 72.59 ;
    LAYER Metal4 ;
        RECT 58.255 69.29 58.785 72.59 ;
    LAYER Metal4 ;
        RECT 59.785 69.29 60.315 72.59 ;
    LAYER Metal4 ;
        RECT 61.315 69.29 61.845 72.59 ;
    LAYER Metal4 ;
        RECT 62.845 69.29 63.3 72.59 ;
    LAYER Metal4 ;
        RECT 64.3 69.29 64.905 72.59 ;
    LAYER Metal4 ;
        RECT 65.905 69.29 66.435 72.59 ;
    LAYER Metal4 ;
        RECT 67.435 69.29 67.965 72.59 ;
    LAYER Metal4 ;
        RECT 68.965 69.29 69.495 72.59 ;
    LAYER Metal4 ;
        RECT 70.93 69.29 71.56 72.59 ;
    LAYER Metal4 ;
        RECT 72.97 69.29 73.60 72.59 ;
    LAYER Metal4 ;
        RECT 74.86 69.29 75.17 72.59 ;
    LAYER Metal4 ;
        RECT 75.44 69.29 75.74 72.59 ;
    LAYER Metal4 ;
        RECT 76.64 69.29 76.94 72.59 ;
    LAYER Metal4 ;
        RECT 77.185 69.29 77.595 72.59 ;
    LAYER Metal4 ;
        RECT 79.18 69.29 79.59 72.59 ;
    LAYER Metal4 ;
        RECT 79.845 69.29 80.255 72.59 ;
    LAYER Metal4 ;
        RECT 81.84 69.29 82. 72.59 ;
    LAYER Metal4 ;
        RECT 82.505 69.29 82.915 72.59 ;
    LAYER Metal4 ;
        RECT 84.5 69.29 84.91 72.59 ;
    LAYER Metal4 ;
        RECT 85.165 69.29 85.5 72.59 ;
    LAYER Metal4 ;
        RECT 87.16 69.29 87.57 72.59 ;
    LAYER Metal4 ;
        RECT 87.8 69.29 88.235 72.59 ;
    LAYER Metal4 ;
        RECT 89.82 69.29 90.23 72.59 ;
    LAYER Metal4 ;
        RECT 90.485 69.29 90.895 72.59 ;
    LAYER Metal4 ;
        RECT 92.48 69.29 92.89 72.59 ;
    LAYER Metal4 ;
        RECT 93.145 69.29 93.555 72.59 ;
    LAYER Metal4 ;
        RECT 95.14 69.29 95.55 72.59 ;
    LAYER Metal4 ;
        RECT 95.805 69.29 96.215 72.59 ;
    LAYER Metal4 ;
        RECT 97.8 69.29 98.21 72.59 ;
    LAYER Metal4 ;
        RECT 98.45 69.29 98. 72.59 ;
    LAYER Metal4 ;
        RECT 98.995 69.29 99.405 72.59 ;
    LAYER Metal4 ;
        RECT 100.99 69.29 101.4 72.59 ;
    LAYER Metal4 ;
        RECT 101.655 69.29 102.065 72.59 ;
    LAYER Metal4 ;
        RECT 103.65 69.29 104.06 72.59 ;
    LAYER Metal4 ;
        RECT 104.315 69.29 104.7 72.59 ;
    LAYER Metal4 ;
        RECT 106.31 69.29 106.72 72.59 ;
    LAYER Metal4 ;
        RECT 106.9 69.29 107.385 72.59 ;
    LAYER Metal4 ;
        RECT 108.97 69.29 109.38 72.59 ;
    LAYER Metal4 ;
        RECT 109.635 69.29 110.045 72.59 ;
    LAYER Metal4 ;
        RECT 111.63 69.29 112.04 72.59 ;
    LAYER Metal4 ;
        RECT 112.295 69.29 112.705 72.59 ;
    LAYER Metal4 ;
        RECT 114.29 69.29 114.7 72.59 ;
    LAYER Metal4 ;
        RECT 114.955 69.29 115.365 72.59 ;
    LAYER Metal4 ;
        RECT 116.95 69.29 117.36 72.59 ;
    LAYER Metal4 ;
        RECT 117.615 69.29 118.0 72.59 ;
    LAYER Metal4 ;
        RECT 119.61 69.29 120.02 72.59 ;
    LAYER Metal4 ;
        RECT 120.26 69.29 120.56 72.59 ;
    LAYER Metal4 ;
        RECT 7.095 6.6 7.395 3.3 ;
    LAYER Metal4 ;
        RECT 8.28 6.6 8.69 3.3 ;
    LAYER Metal4 ;
        RECT 10.36 6.6 11.01 3.3 ;
    LAYER Metal4 ;
        RECT 13.09 6.6 13.74 3.3 ;
    LAYER Metal4 ;
        RECT 15.82 6.6 16.47 3.3 ;
    LAYER Metal4 ;
        RECT 18.14 6.6 18.55 3.3 ;
    LAYER Metal4 ;
        RECT 18.92 6.6 19.33 3.3 ;
    LAYER Metal4 ;
        RECT 21 6.6 21.65 3.3 ;
    LAYER Metal4 ;
        RECT 23.73 6.6 24.38 3.3 ;
    LAYER Metal4 ;
        RECT 26.46 6.6 27.11 3.3 ;
    LAYER Metal4 ;
        RECT 28.78 6.6 29.19 3.3 ;
    LAYER Metal4 ;
        RECT 29.49 6.6 29.79 3.3 ;
    LAYER Metal4 ;
        RECT 30.09 6.6 30.5 3.3 ;
    LAYER Metal4 ;
        RECT 32.17 6.6 32.82 3.3 ;
    LAYER Metal4 ;
        RECT 34.9 6.6 35.55 3.3 ;
    LAYER Metal4 ;
        RECT 37.63 6.6 38.28 3.3 ;
    LAYER Metal4 ;
        RECT 39.95 6.6 40.36 3.3 ;
    LAYER Metal4 ;
        RECT 40.73 6.6 41.14 3.3 ;
    LAYER Metal4 ;
        RECT 42.81 6.6 43.46 3.3 ;
    LAYER Metal4 ;
        RECT 45.54 6.6 46.19 3.3 ;
    LAYER Metal4 ;
        RECT 48.27 6.6 48.92 3.3 ;
    LAYER Metal4 ;
        RECT 50.59 6.6 51 3.3 ;
    LAYER Metal4 ;
        RECT 52.465 6.6 53.095 3.3 ;
    LAYER Metal4 ;
        RECT 55.5 6.6 56.155 3.3 ;
    LAYER Metal4 ;
        RECT 58.585 6.6 59.215 3.3 ;
    LAYER Metal4 ;
        RECT 61.645 6.6 62.2 3.3 ;
    LAYER Metal4 ;
        RECT 64.705 6.6 65.335 3.3 ;
    LAYER Metal4 ;
        RECT 67.765 6.6 68.395 3.3 ;
    LAYER Metal4 ;
        RECT 70.95 6.6 71.36 3.3 ;
    LAYER Metal4 ;
        RECT 72.9 6.6 73.66 3.3 ;
    LAYER Metal4 ;
        RECT 75.18 6.6 75.68 3.3 ;
    LAYER Metal4 ;
        RECT 77.24 6.6 77.65 3.3 ;
    LAYER Metal4 ;
        RECT 79.32 6.6 79.97 3.3 ;
    LAYER Metal4 ;
        RECT 82.05 6.6 82.70 3.3 ;
    LAYER Metal4 ;
        RECT 84.78 6.6 85.43 3.3 ;
    LAYER Metal4 ;
        RECT 87.10 6.6 87.51 3.3 ;
    LAYER Metal4 ;
        RECT 87.88 6.6 88.29 3.3 ;
    LAYER Metal4 ;
        RECT 89.96 6.6 90.61 3.3 ;
    LAYER Metal4 ;
        RECT 92.69 6.6 93.34 3.3 ;
    LAYER Metal4 ;
        RECT 95.42 6.6 96.07 3.3 ;
    LAYER Metal4 ;
        RECT 97.74 6.6 98.15 3.3 ;
    LAYER Metal4 ;
        RECT 98.45 6.6 98. 3.3 ;
    LAYER Metal4 ;
        RECT 99.05 6.6 99.46 3.3 ;
    LAYER Metal4 ;
        RECT 101.13 6.6 101.78 3.3 ;
    LAYER Metal4 ;
        RECT 103.86 6.6 104.51 3.3 ;
    LAYER Metal4 ;
        RECT 106.59 6.6 107.24 3.3 ;
    LAYER Metal4 ;
        RECT 108.91 6.6 109.32 3.3 ;
    LAYER Metal4 ;
        RECT 109.69 6.6 110.10 3.3 ;
    LAYER Metal4 ;
        RECT 111.77 6.6 112.42 3.3 ;
    LAYER Metal4 ;
        RECT 114.50 6.6 115.15 3.3 ;
    LAYER Metal4 ;
        RECT 117.23 6.6 117.88 3.3 ;
    LAYER Metal4 ;
        RECT 119.55 6.6 119.96 3.3 ;
    LAYER Metal4 ;
        RECT 120.84 6.6 121.14 3.3 ;
    END
  END ram_256x16A
END LIBRARY

